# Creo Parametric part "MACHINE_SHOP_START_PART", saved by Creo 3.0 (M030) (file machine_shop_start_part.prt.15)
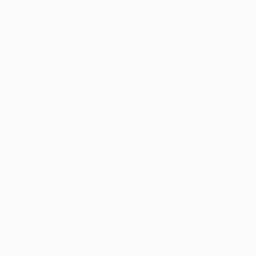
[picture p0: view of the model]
Units: Inch lbm Second (Pro/E Default); INCH, POUND, SECS
Materials in the file: AL6061

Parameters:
  DESCRIPTION = "Part"
  MODELED_BY = "XXXXX"
  YOUR_INITIAL = "XX"
  FINISH = "NONE"
  TEAM_NAME = "XXX XXX"
  MATERIAL = "AL6061"

Created from: INLBS_PART_SOLID.PRT

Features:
  1. datum plane "RIGHT"
  2. datum plane "TOP"
  3. datum plane "FRONT"
  4. coordinate system

Surfaces: 3 plane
